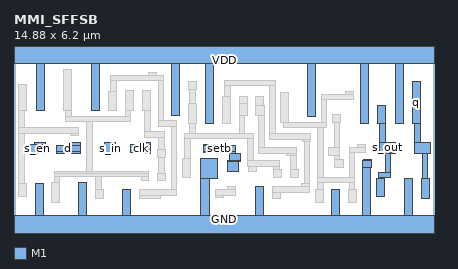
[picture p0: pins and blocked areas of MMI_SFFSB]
MACRO MMI_SFFSB
	CLASS CORE ;
	FOREIGN MMI_SFFSB 0 0 ;
	SIZE 14.88 BY 6.2 ;
	SYMMETRY X Y ;
	SITE CORE1 ;
	PIN d
		DIRECTION input ;
		USE SIGNAL ;
		PORT
			LAYER M1 ;
			RECT 1.5 2.88 1.78 2.9 ;
			LAYER M1 ;
			RECT 1.98 2.88 2.36 2.98 ;
			LAYER M1 ;
			RECT 1.5 2.685 2.36 2.88 ;
			LAYER M1 ;
			RECT 1.5 2.62 1.78 2.685 ;
			LAYER M1 ;
			RECT 1.98 2.6 2.36 2.685 ;
		END
		AntennaGateArea 0.3465 ;
	END d
	PIN GND
		DIRECTION inout ;
		USE GROUND ;
		PORT
			LAYER M1 ;
			RECT 6.625 1.735 7.205 2.44 ;
			LAYER M1 ;
			RECT 12.37 2.365 12.65 2.39 ;
			LAYER M1 ;
			RECT 12.355 2.11 12.65 2.365 ;
			LAYER M1 ;
			RECT 0.75 0.42 1.03 1.525 ;
			LAYER M1 ;
			RECT 2.3 0.42 2.58 1.585 ;
			LAYER M1 ;
			RECT 3.85 0.42 4.13 1.315 ;
			LAYER M1 ;
			RECT 6.625 0.42 6.91 1.735 ;
			LAYER M1 ;
			RECT 8.57 0.42 8.85 1.43 ;
			LAYER M1 ;
			RECT 11.26 0.42 11.54 1.335 ;
			LAYER M1 ;
			RECT 12.355 0.42 12.635 2.11 ;
			LAYER M1 ;
			RECT 13.835 0.42 14.115 1.71 ;
			LAYER M1 ;
			RECT 0 -0.42 14.885 0.42 ;
		END
	END GND
	PIN q
		DIRECTION output ;
		USE SIGNAL ;
		PORT
			LAYER M1 ;
			RECT 14.105 3.68 14.385 5.15 ;
			LAYER M1 ;
			RECT 14.19 2.98 14.385 3.68 ;
			LAYER M1 ;
			RECT 14.19 2.605 14.76 2.98 ;
			LAYER M1 ;
			RECT 14.47 1.71 14.66 2.605 ;
			LAYER M1 ;
			RECT 14.425 1.01 14.705 1.71 ;
		END
		AntennaDiffArea 0.91245 ;
	END q
	PIN s_in
		DIRECTION input ;
		USE SIGNAL ;
		PORT
			LAYER M1 ;
			RECT 3.22 2.6 3.6 2.98 ;
		END
		AntennaGateArea 0.17325 ;
	END s_in
	PIN s_en
		DIRECTION input ;
		USE SIGNAL ;
		PORT
			LAYER M1 ;
			RECT 0.74 2.93 1.12 2.98 ;
			LAYER M1 ;
			RECT 0.555 2.65 1.12 2.93 ;
			LAYER M1 ;
			RECT 0.74 2.6 1.12 2.65 ;
		END
		AntennaGateArea 0.72675 ;
	END s_en
	PIN VDD
		DIRECTION inout ;
		USE POWER ;
		PORT
			LAYER M1 ;
			RECT 0 5.78 14.885 6.62 ;
			LAYER M1 ;
			RECT 0.79 4.11 1.07 5.78 ;
			LAYER M1 ;
			RECT 2.755 4.115 3.035 5.78 ;
			LAYER M1 ;
			RECT 5.59 3.96 5.87 5.78 ;
			LAYER M1 ;
			RECT 6.775 3.675 7.055 5.78 ;
			LAYER M1 ;
			RECT 10.41 3.91 10.69 5.78 ;
			LAYER M1 ;
			RECT 12.28 3.68 12.56 5.78 ;
			LAYER M1 ;
			RECT 13.515 3.68 13.795 5.78 ;
		END
	END VDD
	PIN s_out
		DIRECTION output ;
		USE SIGNAL ;
		PORT
			LAYER M1 ;
			RECT 12.87 3.68 13.15 4.315 ;
			LAYER M1 ;
			RECT 12.96 2.98 13.15 3.68 ;
			LAYER M1 ;
			RECT 12.96 2.655 13.52 2.98 ;
			LAYER M1 ;
			RECT 13.11 2.6 13.52 2.655 ;
			LAYER M1 ;
			RECT 13.145 1.93 13.335 2.6 ;
			LAYER M1 ;
			RECT 12.925 1.74 13.335 1.93 ;
			LAYER M1 ;
			RECT 12.925 1.715 13.115 1.74 ;
			LAYER M1 ;
			RECT 12.835 1.08 13.115 1.715 ;
		END
		AntennaDiffArea 0.588675 ;
	END s_out
	PIN setb
		DIRECTION input ;
		USE SIGNAL ;
		PORT
			LAYER M1 ;
			RECT 6.73 2.88 7.01 2.93 ;
			LAYER M1 ;
			RECT 6.73 2.685 7.84 2.88 ;
			LAYER M1 ;
			RECT 6.73 2.65 7.01 2.685 ;
			LAYER M1 ;
			RECT 7.645 2.61 7.84 2.685 ;
			LAYER M1 ;
			RECT 7.645 2.36 8.03 2.61 ;
			LAYER M1 ;
			RECT 7.56 2.33 8.03 2.36 ;
			LAYER M1 ;
			RECT 7.56 1.98 7.94 2.33 ;
		END
		AntennaGateArea 0.4575 ;
	END setb
	PIN clk
		DIRECTION input ;
		USE CLOCK ;
		PORT
			LAYER M1 ;
			RECT 4.46 2.93 4.84 2.98 ;
			LAYER M1 ;
			RECT 4.15 2.925 4.84 2.93 ;
			LAYER M1 ;
			RECT 4.14 2.645 4.84 2.925 ;
			LAYER M1 ;
			RECT 4.46 2.6 4.84 2.645 ;
		END
		AntennaGateArea 0.44625 ;
	END clk
	OBS
		LAYER M1 ;
		RECT 0.16 4.11 0.44 5.045 ;
		LAYER M1 ;
		RECT 1.75 4.11 2.03 5.58 ;
		LAYER M1 ;
		RECT 4.78 5.365 5.06 5.49 ;
		LAYER M1 ;
		RECT 3.43 5.175 5.295 5.365 ;
		LAYER M1 ;
		RECT 3.43 4.815 3.62 5.175 ;
		LAYER M1 ;
		RECT 3.345 4.115 3.625 4.815 ;
		LAYER M1 ;
		RECT 3.95 4.135 4.23 4.835 ;
		LAYER M1 ;
		RECT 4.54 4.135 4.82 4.835 ;
		LAYER M1 ;
		RECT 0.16 3.515 0.355 4.11 ;
		LAYER M1 ;
		RECT 1.835 3.915 2.03 4.11 ;
		LAYER M1 ;
		RECT 3.955 3.915 4.145 4.135 ;
		LAYER M1 ;
		RECT 1.835 3.725 4.145 3.915 ;
		LAYER M1 ;
		RECT 1.99 3.515 2.27 3.525 ;
		LAYER M1 ;
		RECT 0.16 3.325 2.27 3.515 ;
		LAYER M1 ;
		RECT 0.16 1.525 0.355 3.325 ;
		LAYER M1 ;
		RECT 1.99 3.245 2.27 3.325 ;
		LAYER M1 ;
		RECT 2.58 1.98 2.775 3.725 ;
		LAYER M1 ;
		RECT 4.63 3.37 4.82 4.135 ;
		LAYER M1 ;
		RECT 5.105 3.76 5.295 5.175 ;
		LAYER M1 ;
		RECT 6.185 4.885 6.465 5.165 ;
		LAYER M1 ;
		RECT 6.23 4.375 6.425 4.885 ;
		LAYER M1 ;
		RECT 5.105 3.57 5.765 3.76 ;
		LAYER M1 ;
		RECT 6.185 3.675 6.465 4.375 ;
		LAYER M1 ;
		RECT 7.465 5.01 9.25 5.205 ;
		LAYER M1 ;
		RECT 7.465 4.61 7.66 5.01 ;
		LAYER M1 ;
		RECT 7.38 3.675 7.66 4.61 ;
		LAYER M1 ;
		RECT 7.98 4.375 8.26 4.635 ;
		LAYER M1 ;
		RECT 7.975 3.935 8.26 4.375 ;
		LAYER M1 ;
		RECT 8.57 4.29 8.85 4.635 ;
		LAYER M1 ;
		RECT 8.57 3.935 8.86 4.29 ;
		LAYER M1 ;
		RECT 4.63 3.18 5.325 3.37 ;
		LAYER M1 ;
		RECT 5.135 2.735 5.325 3.18 ;
		LAYER M1 ;
		RECT 5.095 2.455 5.375 2.735 ;
		LAYER M1 ;
		RECT 1.43 1.91 4.775 1.98 ;
		LAYER M1 ;
		RECT 5.135 1.91 5.325 2.455 ;
		LAYER M1 ;
		RECT 1.43 1.785 4.78 1.91 ;
		LAYER M1 ;
		RECT 1.43 1.585 1.62 1.785 ;
		LAYER M1 ;
		RECT 0.16 1.09 0.44 1.525 ;
		LAYER M1 ;
		RECT 1.34 0.885 1.62 1.585 ;
		LAYER M1 ;
		RECT 2.89 1.315 3.085 1.785 ;
		LAYER M1 ;
		RECT 4.5 1.63 4.78 1.785 ;
		LAYER M1 ;
		RECT 5.09 1.63 5.37 1.91 ;
		LAYER M1 ;
		RECT 5.575 1.315 5.765 3.57 ;
		LAYER M1 ;
		RECT 6.23 3.325 6.425 3.675 ;
		LAYER M1 ;
		RECT 7.975 3.325 8.165 3.935 ;
		LAYER M1 ;
		RECT 6.05 3.13 8.47 3.325 ;
		LAYER M1 ;
		RECT 6.05 2.44 6.245 3.13 ;
		LAYER M1 ;
		RECT 5.965 1.74 6.245 2.44 ;
		LAYER M1 ;
		RECT 2.89 1 3.17 1.315 ;
		LAYER M1 ;
		RECT 4.44 1.125 5.765 1.315 ;
		LAYER M1 ;
		RECT 8.28 2.35 8.47 3.13 ;
		LAYER M1 ;
		RECT 8.67 2.81 8.86 3.935 ;
		LAYER M1 ;
		RECT 9.06 3.3 9.25 5.01 ;
		LAYER M1 ;
		RECT 9.45 3.71 9.73 4.77 ;
		LAYER M1 ;
		RECT 11.76 4.7 12.04 4.79 ;
		LAYER M1 ;
		RECT 10.89 4.51 12.04 4.7 ;
		LAYER M1 ;
		RECT 9.535 3.705 9.73 3.71 ;
		LAYER M1 ;
		RECT 10.89 3.705 11.08 4.51 ;
		LAYER M1 ;
		RECT 11.28 3.705 11.56 3.985 ;
		LAYER M1 ;
		RECT 9.535 3.515 11.08 3.705 ;
		LAYER M1 ;
		RECT 10.215 3.3 10.495 3.31 ;
		LAYER M1 ;
		RECT 9.06 3.105 10.495 3.3 ;
		LAYER M1 ;
		RECT 10.215 3.03 10.495 3.105 ;
		LAYER M1 ;
		RECT 9.64 2.81 9.92 2.825 ;
		LAYER M1 ;
		RECT 8.67 2.62 9.995 2.81 ;
		LAYER M1 ;
		RECT 9.64 2.545 9.995 2.62 ;
		LAYER M1 ;
		RECT 8.28 2.16 9.39 2.35 ;
		LAYER M1 ;
		RECT 8.325 1.965 8.605 2.16 ;
		LAYER M1 ;
		RECT 9.195 2.02 9.39 2.16 ;
		LAYER M1 ;
		RECT 9.8 2.02 9.995 2.545 ;
		LAYER M1 ;
		RECT 9.195 1.755 9.485 2.02 ;
		LAYER M1 ;
		RECT 9.205 1.74 9.485 1.755 ;
		LAYER M1 ;
		RECT 9.795 1.74 10.075 2.02 ;
		LAYER M1 ;
		RECT 4.44 1 5.18 1.125 ;
		LAYER M1 ;
		RECT 10.28 1.54 10.47 3.03 ;
		LAYER M1 ;
		RECT 10.19 1.43 10.47 1.54 ;
		LAYER M1 ;
		RECT 7.56 1.315 7.84 1.425 ;
		LAYER M1 ;
		RECT 7.125 1.125 7.84 1.315 ;
		LAYER M1 ;
		RECT 7.125 1.035 7.405 1.125 ;
		LAYER M1 ;
		RECT 9.16 1.235 10.47 1.43 ;
		LAYER M1 ;
		RECT 10.755 1.75 10.95 3.515 ;
		LAYER M1 ;
		RECT 11.355 2.825 11.545 3.705 ;
		LAYER M1 ;
		RECT 11.155 2.545 11.545 2.825 ;
		LAYER M1 ;
		RECT 12.175 2.82 12.455 2.91 ;
		LAYER M1 ;
		RECT 11.355 2.39 11.545 2.545 ;
		LAYER M1 ;
		RECT 11.89 2.63 12.455 2.82 ;
		LAYER M1 ;
		RECT 11.89 2.625 12.43 2.63 ;
		LAYER M1 ;
		RECT 11.355 2.11 11.69 2.39 ;
		LAYER M1 ;
		RECT 11.89 1.75 12.08 2.625 ;
		LAYER M1 ;
		RECT 10.755 1.56 12.08 1.75 ;
		LAYER M1 ;
		RECT 10.755 1.335 10.95 1.56 ;
		LAYER M1 ;
		RECT 11.89 1.335 12.08 1.56 ;
		LAYER M1 ;
		RECT 9.16 0.995 9.44 1.235 ;
		LAYER M1 ;
		RECT 10.67 0.885 10.95 1.335 ;
		LAYER M1 ;
		RECT 11.85 0.885 12.13 1.335 ;
	END
END MMI_SFFSB
